One B-rep face of a CAD part: STEP entity #113.
In plain terms, the planar face has unit normal (1, 0, 0).
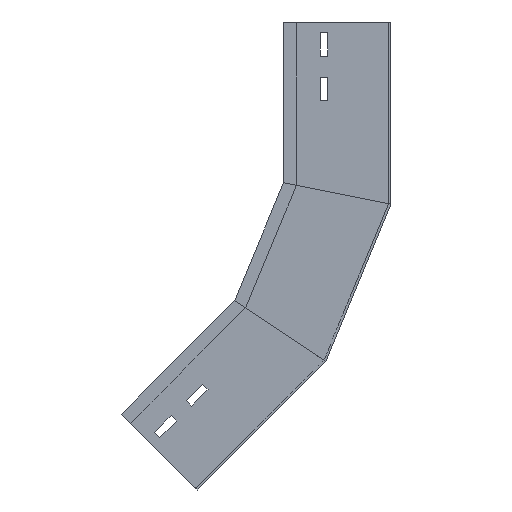
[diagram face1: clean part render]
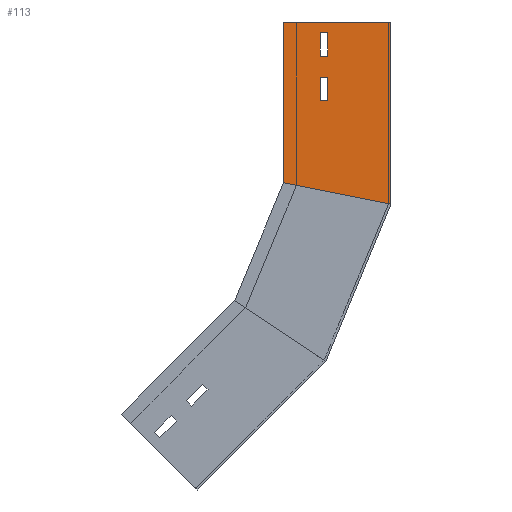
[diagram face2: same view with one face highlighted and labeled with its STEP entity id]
Its self-contained STEP definition (entity closure, numbers rounded to 3 decimals):
#12 = EDGE_CURVE ( 'NONE', #541, #589, #302, .T. ) ;
#31 = ORIENTED_EDGE ( 'NONE', *, *, #917, .F. ) ;
#38 = CARTESIAN_POINT ( 'NONE',  ( 0., 175.274, -337.315 ) ) ;
#52 = DIRECTION ( 'NONE',  ( 0., -0.707, -0.707 ) ) ;
#58 = DIRECTION ( 'NONE',  ( 0., -0.707, 0.707 ) ) ;
#65 = EDGE_LOOP ( 'NONE', ( #1054, #1111, #1135, #106 ) ) ;
#78 = LINE ( 'NONE', #865, #1303 ) ;
#94 = VECTOR ( 'NONE', #939, 1000. ) ;
#106 = ORIENTED_EDGE ( 'NONE', *, *, #138, .F. ) ;
#113 = ADVANCED_FACE ( 'NONE', ( #142, #133, #148 ), #372, .F. ) ;
#114 = EDGE_CURVE ( 'NONE', #235, #1034, #583, .T. ) ;
#120 = EDGE_CURVE ( 'NONE', #1381, #504, #591, .T. ) ;
#133 = FACE_BOUND ( 'NONE', #65, .T. ) ;
#138 = EDGE_CURVE ( 'NONE', #906, #1129, #233, .T. ) ;
#142 = FACE_BOUND ( 'NONE', #1287, .T. ) ;
#148 = FACE_OUTER_BOUND ( 'NONE', #502, .T. ) ;
#177 = DIRECTION ( 'NONE',  ( 0., 0.707, 0.707 ) ) ;
#200 = VERTEX_POINT ( 'NONE', #1433 ) ;
#233 = LINE ( 'NONE', #38, #94 ) ;
#235 = VERTEX_POINT ( 'NONE', #739 ) ;
#256 = CARTESIAN_POINT ( 'NONE',  ( 0., 170.324, -342.265 ) ) ;
#302 = LINE ( 'NONE', #649, #971 ) ;
#305 = LINE ( 'NONE', #1465, #1382 ) ;
#311 = DIRECTION ( 'NONE',  ( 0., 0.707, -0.707 ) ) ;
#327 = CARTESIAN_POINT ( 'NONE',  ( 0., 131.366, -245.324 ) ) ;
#345 = DIRECTION ( 'NONE',  ( 0., 0., 1. ) ) ;
#364 = ORIENTED_EDGE ( 'NONE', *, *, #1307, .F. ) ;
#372 = PLANE ( 'NONE',  #1072 ) ;
#395 = EDGE_CURVE ( 'NONE', #664, #906, #620, .T. ) ;
#397 = LINE ( 'NONE', #327, #669 ) ;
#399 = ORIENTED_EDGE ( 'NONE', *, *, #659, .T. ) ;
#400 = CARTESIAN_POINT ( 'NONE',  ( 0., 251.291, -365.25 ) ) ;
#402 = EDGE_CURVE ( 'NONE', #200, #696, #397, .T. ) ;
#405 = LINE ( 'NONE', #526, #651 ) ;
#435 = DIRECTION ( 'NONE',  ( 0., 0.707, 0.707 ) ) ;
#502 = EDGE_LOOP ( 'NONE', ( #566, #1327, #399, #596 ) ) ;
#504 = VERTEX_POINT ( 'NONE', #938 ) ;
#508 = CARTESIAN_POINT ( 'NONE',  ( 0., 190.83, -352.872 ) ) ;
#526 = CARTESIAN_POINT ( 'NONE',  ( 0., 185.88, -357.821 ) ) ;
#541 = VERTEX_POINT ( 'NONE', #594 ) ;
#566 = ORIENTED_EDGE ( 'NONE', *, *, #1203, .T. ) ;
#583 = LINE ( 'NONE', #1300, #1372 ) ;
#589 = VERTEX_POINT ( 'NONE', #1415 ) ;
#591 = LINE ( 'NONE', #1149, #691 ) ;
#594 = CARTESIAN_POINT ( 'NONE',  ( 0., 199.789, -371.73 ) ) ;
#596 = ORIENTED_EDGE ( 'NONE', *, *, #402, .F. ) ;
#601 = CARTESIAN_POINT ( 'NONE',  ( 0., 185.88, -357.821 ) ) ;
#618 = CARTESIAN_POINT ( 'NONE',  ( 0., 204.739, -366.78 ) ) ;
#620 = LINE ( 'NONE', #508, #1321 ) ;
#632 = VECTOR ( 'NONE', #1333, 1000. ) ;
#649 = CARTESIAN_POINT ( 'NONE',  ( 0., 215.346, -387.287 ) ) ;
#651 = VECTOR ( 'NONE', #311, 1000. ) ;
#653 = DIRECTION ( 'NONE',  ( 0., 0.707, 0.707 ) ) ;
#655 = CARTESIAN_POINT ( 'NONE',  ( 0., 175.274, -337.315 ) ) ;
#659 = EDGE_CURVE ( 'NONE', #504, #696, #893, .T. ) ;
#664 = VERTEX_POINT ( 'NONE', #1107 ) ;
#666 = ORIENTED_EDGE ( 'NONE', *, *, #12, .F. ) ;
#669 = VECTOR ( 'NONE', #683, 1000. ) ;
#683 = DIRECTION ( 'NONE',  ( 0., 0.707, -0.707 ) ) ;
#691 = VECTOR ( 'NONE', #1413, 1000. ) ;
#696 = VERTEX_POINT ( 'NONE', #400 ) ;
#717 = EDGE_CURVE ( 'NONE', #1368, #664, #78, .T. ) ;
#739 = CARTESIAN_POINT ( 'NONE',  ( 0., 220.295, -382.337 ) ) ;
#753 = VECTOR ( 'NONE', #653, 1000. ) ;
#853 = CARTESIAN_POINT ( 'NONE',  ( 0., 86.366, -298.856 ) ) ;
#861 = DIRECTION ( 'NONE',  ( 0., 0.707, -0.707 ) ) ;
#865 = CARTESIAN_POINT ( 'NONE',  ( 0., 190.83, -352.872 ) ) ;
#880 = ORIENTED_EDGE ( 'NONE', *, *, #114, .F. ) ;
#893 = LINE ( 'NONE', #1364, #753 ) ;
#906 = VERTEX_POINT ( 'NONE', #655 ) ;
#917 = EDGE_CURVE ( 'NONE', #589, #235, #305, .T. ) ;
#922 = EDGE_CURVE ( 'NONE', #1129, #1368, #405, .T. ) ;
#935 = DIRECTION ( 'NONE',  ( 0., -0.707, 0.707 ) ) ;
#938 = CARTESIAN_POINT ( 'NONE',  ( 0., 180.581, -435.96 ) ) ;
#939 = DIRECTION ( 'NONE',  ( 0., -0.707, -0.707 ) ) ;
#971 = VECTOR ( 'NONE', #861, 1000. ) ;
#1034 = VERTEX_POINT ( 'NONE', #1344 ) ;
#1054 = ORIENTED_EDGE ( 'NONE', *, *, #395, .F. ) ;
#1072 = AXIS2_PLACEMENT_3D ( 'NONE', #1178, #1395, #345 ) ;
#1107 = CARTESIAN_POINT ( 'NONE',  ( 0., 190.83, -352.872 ) ) ;
#1111 = ORIENTED_EDGE ( 'NONE', *, *, #717, .F. ) ;
#1120 = CARTESIAN_POINT ( 'NONE',  ( 0., 60.655, -316.035 ) ) ;
#1129 = VERTEX_POINT ( 'NONE', #256 ) ;
#1135 = ORIENTED_EDGE ( 'NONE', *, *, #922, .F. ) ;
#1149 = CARTESIAN_POINT ( 'NONE',  ( 0., 60.655, -316.035 ) ) ;
#1164 = LINE ( 'NONE', #853, #632 ) ;
#1178 = CARTESIAN_POINT ( 'NONE',  ( 0., 60.655, -316.035 ) ) ;
#1184 = LINE ( 'NONE', #618, #1240 ) ;
#1203 = EDGE_CURVE ( 'NONE', #200, #1381, #1164, .T. ) ;
#1240 = VECTOR ( 'NONE', #52, 1000. ) ;
#1287 = EDGE_LOOP ( 'NONE', ( #880, #31, #666, #364 ) ) ;
#1300 = CARTESIAN_POINT ( 'NONE',  ( 0., 220.295, -382.337 ) ) ;
#1303 = VECTOR ( 'NONE', #435, 1000. ) ;
#1307 = EDGE_CURVE ( 'NONE', #1034, #541, #1184, .T. ) ;
#1321 = VECTOR ( 'NONE', #58, 1000. ) ;
#1327 = ORIENTED_EDGE ( 'NONE', *, *, #120, .T. ) ;
#1333 = DIRECTION ( 'NONE',  ( 0., -0.831, -0.556 ) ) ;
#1344 = CARTESIAN_POINT ( 'NONE',  ( 0., 204.739, -366.78 ) ) ;
#1364 = CARTESIAN_POINT ( 'NONE',  ( 0., 180.581, -435.96 ) ) ;
#1368 = VERTEX_POINT ( 'NONE', #601 ) ;
#1372 = VECTOR ( 'NONE', #935, 1000. ) ;
#1381 = VERTEX_POINT ( 'NONE', #1120 ) ;
#1382 = VECTOR ( 'NONE', #177, 1000. ) ;
#1395 = DIRECTION ( 'NONE',  ( -1., 0., 0. ) ) ;
#1413 = DIRECTION ( 'NONE',  ( 0., 0.707, -0.707 ) ) ;
#1415 = CARTESIAN_POINT ( 'NONE',  ( 0., 215.346, -387.287 ) ) ;
#1433 = CARTESIAN_POINT ( 'NONE',  ( 0., 145.431, -259.389 ) ) ;
#1465 = CARTESIAN_POINT ( 'NONE',  ( 0., 220.295, -382.337 ) ) ;
